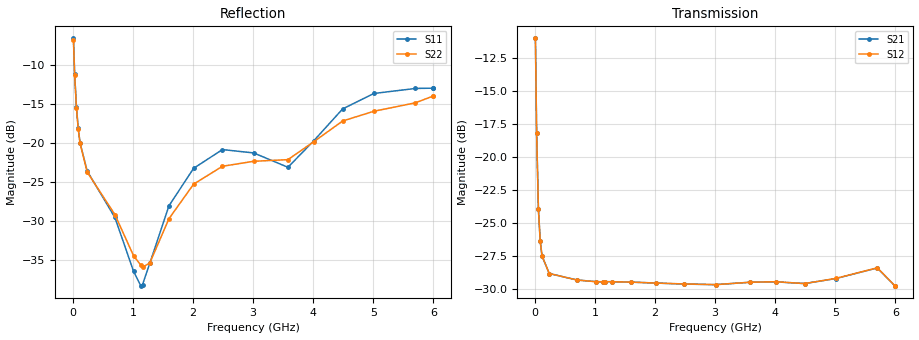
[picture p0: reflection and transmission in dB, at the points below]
! Integrated Device Technology
! Corporate Headquarters
! 6024 Silver Creek Valley Road
! San Jose, CA 95138  USA
! Phone:  1-408-284-8200
! Toll Free:  1-800-223-1366
! Webpage:  http://www.idt.com/
! Timing and RF Division
! 515 Groton Road, Suite 102
! Westford, MA 01886-6024
! Device:  F1951
! Description: 6-bit 0.5 dB Digital Step Attenuator
! Frequency:  100.0 -  4000.00 MHz
! Package:  4x4 mm Thin QFN Plastic Package: 24 pin
! Ports:  2 RF, 6 DC
!  Pin  1  = NC
!  Pin  2  = RF1  =  Port 1
!  Pin  3  = GND
!  Pin  4  = NC
!  Pin  5  = Serial Data Out (SDO)
!  Pin  6  = NC
!  Pin  7  = Reset Bar ( RSTb)
!  Pin  8  = Clock (CLK)
!  Pin  9  = Chip Select Bar (CSb)
!  Pin 10  = NC
!  Pin 11  = Serial Data In (SDI)
!  Pin 12  = NC
!  Pin 13  = NC
!  Pin 14  = VDD
!  Pin 15  = NC
!  Pin 16  = GND
!  Pin 17  = RF2  =  Port 2
!  Pin 18  = NC
!  Pin 19  = GND
!  Pin 20  = GND
!  Pin 21  = GND
!  Pin 22  = GND
!  Pin 23  = GND
!  Pin 24  = GND
! State:  57
! Atten State:  28.5 dB
! Voltage:  +3.30 Volts
! Current:  0.490 mA
! Data:  The device was measured on a F195X evaluation board which has
!  individual transmission lines to the RF pins.  Data was collected
!  de-embedded using a Automatic Fixture Removal [AFR] (Keysight Technologies).
!  The reference plane is the edge of the package pin.
! Misc:  Lot Code  1225BCA
!  Action Tracker AT0399
! Date Measured:  2018-09-13
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# GHz S dB R 50
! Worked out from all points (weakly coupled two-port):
!   600 points, 10 MHz to 6 GHz, reference 50 ohm
!   highest |S21| = -11.04 dB at 10 MHz (marker M1); lowest = -29.7 dB at 5.99 GHz (marker M2)
!   lowest |S11| = -38.3 dB at 1.13 GHz (marker M3), VSWR 1.02, Z = 48.8 + j0.228 ohm
!   |S11| at or under -10 dB: 24.32 MHz to end of sweep
!   |S22| runs from -36.1 to -6.8 dB; largest |S21 - S12| = 0.00017
!   S11 on the Smith chart (normalised r, x): 10 MHz: 1.77, -1.18; 30 MHz: 1.12, -0.60; 60 MHz: 0.98, -0.34; 1.16 GHz: 0.98, +0.01; 6 GHz: 0.81, +0.37
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0.01  -6.61 -33.9  -11.04 -40.0  -11.04 -40.0  -6.77 -33.9
0.03  -11.16 -63.0  -18.17 -62.7  -18.17 -62.7  -11.27 -62.8
0.06  -15.42 -83.0  -23.95 -56.0  -23.96 -56.0  -15.53 -82.9
0.09  -18.15 -95.0  -26.36 -45.2  -26.36 -45.2  -18.23 -95.1
0.12  -20.00 -103.9  -27.48 -37.2  -27.48 -37.2  -20.06 -103.7
0.24  -23.63 -123.0  -28.80 -22.3  -28.80 -22.2  -23.76 -123.0
0.7  -29.56 -136.6  -29.29 -14.5  -29.29 -14.6  -29.19 -139.0
1.01  -36.45 -158.4  -29.41 -15.7  -29.42 -15.7  -34.45 -154.2
1.13  -38.30 168.9  -29.43 -16.2  -29.42 -16.2  -35.66 -171.2
1.16  -38.15 159.3  -29.42 -16.4  -29.42 -16.4  -35.93 -176.7
1.28  -35.45 130.0  -29.42 -17.2  -29.42 -17.2  -35.40 160.5
1.6  -28.06 115.3  -29.45 -19.8  -29.45 -19.8  -29.71 134.6
2.01  -23.26 123.0  -29.52 -23.6  -29.52 -23.5  -25.29 135.1
2.49  -20.86 135.8  -29.60 -27.8  -29.59 -27.8  -23.00 142.1
3.01  -21.29 145.6  -29.64 -32.1  -29.64 -32.1  -22.36 145.4
3.58  -23.13 124.4  -29.46 -36.9  -29.46 -36.9  -22.15 128.5
4.01  -19.73 100.4  -29.43 -40.7  -29.42 -40.6  -19.85 116.4
4.49  -15.65 98.8  -29.56 -44.3  -29.56 -44.3  -17.20 114.5
5.01  -13.67 107.6  -29.18 -45.8  -29.17 -45.8  -15.95 116.8
5.7  -13.03 112.5  -28.38 -57.4  -28.37 -57.4  -14.87 109.6
5.99  -12.99 106.6  -29.72 -59.0  -29.72 -59.0  -14.02 105.9
6  -12.99 106.3  -29.71 -58.4  -29.71 -58.4  -13.98 105.8
